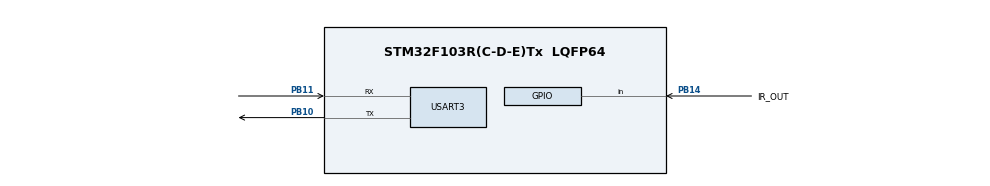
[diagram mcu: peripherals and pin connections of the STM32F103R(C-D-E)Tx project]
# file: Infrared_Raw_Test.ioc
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Mcu.Family=STM32F1
Mcu.Name=STM32F103R(C-D-E)Tx
Mcu.Package=LQFP64
NVIC.PriorityGroup=NVIC_PRIORITYGROUP_4
PA13.Mode=Serial_Wire
PA13.Signal=SYS_JTMS-SWDIO
PA14.Mode=Serial_Wire
PA14.Signal=SYS_JTCK-SWCLK
PB10.Mode=Asynchronous
PB10.Signal=USART3_TX
PB11.Mode=Asynchronous
PB11.Signal=USART3_RX
PB14.GPIO_Label=IR_OUT
PB14.GPIO_PuPd=GPIO_NOPULL
PB14.Signal=GPIO_Input
PD0-OSC_IN.Mode=HSE-External-Oscillator
PD0-OSC_IN.Signal=RCC_OSC_IN
PD1-OSC_OUT.Mode=HSE-External-Oscillator
PD1-OSC_OUT.Signal=RCC_OSC_OUT
ProjectManager.HeapSize=0x200
ProjectManager.StackSize=0x400
ProjectManager.TargetToolchain=MDK-ARM V5.32
RCC.AHBFreq_Value=72000000
RCC.APB1CLKDivider=RCC_HCLK_DIV2
RCC.APB1Freq_Value=72000000
RCC.APB2Freq_Value=72000000
RCC.HCLKFreq_Value=72000000
RCC.PLLMUL=RCC_PLL_MUL9
RCC.PLLSourceVirtual=RCC_PLLSOURCE_HSE
RCC.SYSCLKFreq_VALUE=72000000
RCC.SYSCLKSource=RCC_SYSCLKSOURCE_PLLCLK
USART3.VirtualMode=VM_ASYNC
board=custom

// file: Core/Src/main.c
/* USER CODE BEGIN Header */
/**
  ******************************************************************************
  * @file           : main.c
  * @brief          : Main program body
  ******************************************************************************
  */
/* USER CODE END Header */
#include "main.h"

/* USER CODE BEGIN Includes */
#include "App_InfraredRawTest.h"
/* USER CODE END Includes */

UART_HandleTypeDef huart3;

void SystemClock_Config(void);
static void MX_GPIO_Init(void);
static void MX_USART3_UART_Init(void);

int main(void)
{
  HAL_Init();
  SystemClock_Config();

  MX_GPIO_Init();
  MX_USART3_UART_Init();
  App_InfraredRawTest_Init();

  while (1)
  {
    App_InfraredRawTest_Task();
  }
}

void SystemClock_Config(void)
{
  RCC_OscInitTypeDef RCC_OscInitStruct = {0};
  RCC_ClkInitTypeDef RCC_ClkInitStruct = {0};

  RCC_OscInitStruct.OscillatorType = RCC_OSCILLATORTYPE_HSE;
  RCC_OscInitStruct.HSEState = RCC_HSE_ON;
  RCC_OscInitStruct.HSEPredivValue = RCC_HSE_PREDIV_DIV1;
  RCC_OscInitStruct.HSIState = RCC_HSI_ON;
  RCC_OscInitStruct.PLL.PLLState = RCC_PLL_ON;
  RCC_OscInitStruct.PLL.PLLSource = RCC_PLLSOURCE_HSE;
  RCC_OscInitStruct.PLL.PLLMUL = RCC_PLL_MUL9;
  if (HAL_RCC_OscConfig(&RCC_OscInitStruct) != HAL_OK)
  {
    Error_Handler();
  }

  RCC_ClkInitStruct.ClockType = RCC_CLOCKTYPE_HCLK | RCC_CLOCKTYPE_SYSCLK |
                                RCC_CLOCKTYPE_PCLK1 | RCC_CLOCKTYPE_PCLK2;
  RCC_ClkInitStruct.SYSCLKSource = RCC_SYSCLKSOURCE_PLLCLK;
  RCC_ClkInitStruct.AHBCLKDivider = RCC_SYSCLK_DIV1;
  RCC_ClkInitStruct.APB1CLKDivider = RCC_HCLK_DIV2;
  RCC_ClkInitStruct.APB2CLKDivider = RCC_HCLK_DIV1;
  if (HAL_RCC_ClockConfig(&RCC_ClkInitStruct, FLASH_LATENCY_2) != HAL_OK)
  {
    Error_Handler();
  }
}

static void MX_USART3_UART_Init(void)
{
  huart3.Instance = USART3;
  huart3.Init.BaudRate = 115200;
  huart3.Init.WordLength = UART_WORDLENGTH_8B;
  huart3.Init.StopBits = UART_STOPBITS_1;
  huart3.Init.Parity = UART_PARITY_NONE;
  huart3.Init.Mode = UART_MODE_TX_RX;
  huart3.Init.HwFlowCtl = UART_HWCONTROL_NONE;
  huart3.Init.OverSampling = UART_OVERSAMPLING_16;
  if (HAL_UART_Init(&huart3) != HAL_OK)
  {
    Error_Handler();
  }
}

static void MX_GPIO_Init(void)
{
  GPIO_InitTypeDef GPIO_InitStruct = {0};

  __HAL_RCC_GPIOB_CLK_ENABLE();

  GPIO_InitStruct.Pin = IR_OUT_Pin;
  GPIO_InitStruct.Mode = GPIO_MODE_INPUT;
  GPIO_InitStruct.Pull = GPIO_NOPULL;
  HAL_GPIO_Init(IR_OUT_GPIO_Port, &GPIO_InitStruct);
}

void Error_Handler(void)
{
  __disable_irq();
  while (1)
  {
  }
}
